VERSION 5.8 ;
DIVIDERCHAR "/" ;
BUSBITCHARS "[]" ;
UNITS
  DATABASE MICRONS 1000 ;
END UNITS
MANUFACTURINGGRID 0.001 ;
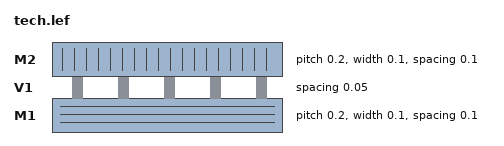
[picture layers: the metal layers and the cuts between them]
LAYER M1
  TYPE ROUTING ;
  DIRECTION HORIZONTAL ;
  PITCH 0.200 ;
  WIDTH 0.100 ;
  AREA 0.040 ;
  SPACING 0.100 ;
END M1
LAYER V1
  TYPE CUT ;
  SPACING 0.050 ;
END V1
LAYER M2
  TYPE ROUTING ;
  DIRECTION VERTICAL ;
  PITCH 0.200 ;
  WIDTH 0.100 ;
  AREA 0.040 ;
  SPACING 0.100 ;
END M2
VIA V12 DEFAULT
  LAYER M1 ;
    RECT -0.060 -0.060 0.060 0.060 ;
  LAYER V1 ;
    RECT -0.025 -0.025 0.025 0.025 ;
  LAYER M2 ;
    RECT -0.060 -0.060 0.060 0.060 ;
END V12
SITE CORE
  CLASS CORE ;
  SIZE 1.000 BY 1.000 ;
  SYMMETRY X Y ;
END CORE
END LIBRARY
